One B-rep face of a CAD part: STEP entity #26644.
In plain terms, the planar face has unit normal (0, 0, -1).
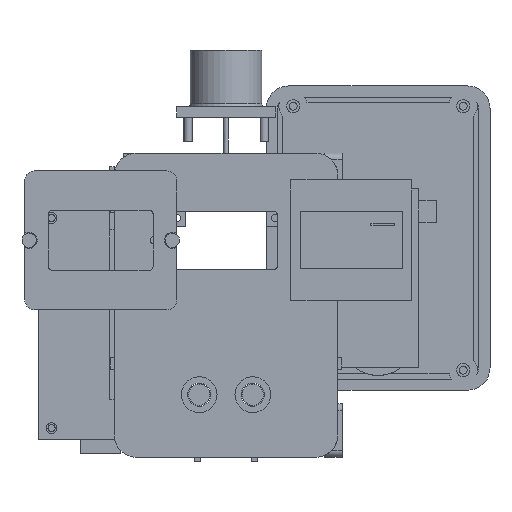
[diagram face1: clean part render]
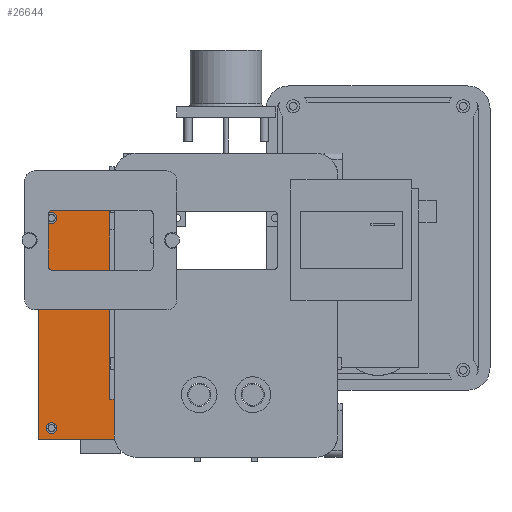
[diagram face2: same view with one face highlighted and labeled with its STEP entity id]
Its self-contained STEP definition (entity closure, numbers rounded to 3 decimals):
#26231 = VERTEX_POINT('',#26232);
#26232 = CARTESIAN_POINT('',(-14.,-30.,9.));
#26241 = PLANE('',#26242);
#26242 = AXIS2_PLACEMENT_3D('',#26243,#26244,#26245);
#26243 = CARTESIAN_POINT('',(-14.,-30.,9.));
#26244 = DIRECTION('',(1.,0.,-0.));
#26245 = DIRECTION('',(0.,0.,1.));
#26253 = PLANE('',#26254);
#26254 = AXIS2_PLACEMENT_3D('',#26255,#26256,#26257);
#26255 = CARTESIAN_POINT('',(-14.,-30.,9.));
#26256 = DIRECTION('',(-0.,1.,0.));
#26257 = DIRECTION('',(0.,0.,1.));
#26265 = EDGE_CURVE('',#26231,#26266,#26268,.T.);
#26266 = VERTEX_POINT('',#26267);
#26267 = CARTESIAN_POINT('',(-14.,22.,9.));
#26268 = SURFACE_CURVE('',#26269,(#26273,#26280),.PCURVE_S1.);
#26269 = LINE('',#26270,#26271);
#26270 = CARTESIAN_POINT('',(-14.,-30.,9.));
#26271 = VECTOR('',#26272,1.);
#26272 = DIRECTION('',(-0.,1.,0.));
#26273 = PCURVE('',#26241,#26274);
#26274 = DEFINITIONAL_REPRESENTATION('',(#26275),#26279);
#26275 = LINE('',#26276,#26277);
#26276 = CARTESIAN_POINT('',(0.,0.));
#26277 = VECTOR('',#26278,1.);
#26278 = DIRECTION('',(0.,-1.));
#26279 = ( GEOMETRIC_REPRESENTATION_CONTEXT(2) 
PARAMETRIC_REPRESENTATION_CONTEXT() REPRESENTATION_CONTEXT('2D SPACE',''
  ) );
#26280 = PCURVE('',#26281,#26286);
#26281 = PLANE('',#26282);
#26282 = AXIS2_PLACEMENT_3D('',#26283,#26284,#26285);
#26283 = CARTESIAN_POINT('',(-14.,-30.,9.));
#26284 = DIRECTION('',(0.,0.,1.));
#26285 = DIRECTION('',(1.,0.,-0.));
#26286 = DEFINITIONAL_REPRESENTATION('',(#26287),#26291);
#26287 = LINE('',#26288,#26289);
#26288 = CARTESIAN_POINT('',(0.,0.));
#26289 = VECTOR('',#26290,1.);
#26290 = DIRECTION('',(0.,1.));
#26291 = ( GEOMETRIC_REPRESENTATION_CONTEXT(2) 
PARAMETRIC_REPRESENTATION_CONTEXT() REPRESENTATION_CONTEXT('2D SPACE',''
  ) );
#26309 = PLANE('',#26310);
#26310 = AXIS2_PLACEMENT_3D('',#26311,#26312,#26313);
#26311 = CARTESIAN_POINT('',(-14.,22.,9.));
#26312 = DIRECTION('',(-0.,1.,0.));
#26313 = DIRECTION('',(0.,0.,1.));
#26350 = EDGE_CURVE('',#26231,#26351,#26353,.T.);
#26351 = VERTEX_POINT('',#26352);
#26352 = CARTESIAN_POINT('',(14.,-30.,9.));
#26353 = SURFACE_CURVE('',#26354,(#26358,#26365),.PCURVE_S1.);
#26354 = LINE('',#26355,#26356);
#26355 = CARTESIAN_POINT('',(-14.,-30.,9.));
#26356 = VECTOR('',#26357,1.);
#26357 = DIRECTION('',(1.,0.,-0.));
#26358 = PCURVE('',#26253,#26359);
#26359 = DEFINITIONAL_REPRESENTATION('',(#26360),#26364);
#26360 = LINE('',#26361,#26362);
#26361 = CARTESIAN_POINT('',(0.,0.));
#26362 = VECTOR('',#26363,1.);
#26363 = DIRECTION('',(0.,1.));
#26364 = ( GEOMETRIC_REPRESENTATION_CONTEXT(2) 
PARAMETRIC_REPRESENTATION_CONTEXT() REPRESENTATION_CONTEXT('2D SPACE',''
  ) );
#26365 = PCURVE('',#26281,#26366);
#26366 = DEFINITIONAL_REPRESENTATION('',(#26367),#26371);
#26367 = LINE('',#26368,#26369);
#26368 = CARTESIAN_POINT('',(0.,0.));
#26369 = VECTOR('',#26370,1.);
#26370 = DIRECTION('',(1.,0.));
#26371 = ( GEOMETRIC_REPRESENTATION_CONTEXT(2) 
PARAMETRIC_REPRESENTATION_CONTEXT() REPRESENTATION_CONTEXT('2D SPACE',''
  ) );
#26411 = PLANE('',#26412);
#26412 = AXIS2_PLACEMENT_3D('',#26413,#26414,#26415);
#26413 = CARTESIAN_POINT('',(14.,-30.,9.));
#26414 = DIRECTION('',(1.,0.,-0.));
#26415 = DIRECTION('',(0.,0.,1.));
#26491 = CYLINDRICAL_SURFACE('',#26492,1.2);
#26492 = AXIS2_PLACEMENT_3D('',#26493,#26494,#26495);
#26493 = CARTESIAN_POINT('',(-11.,-27.5,8.95));
#26494 = DIRECTION('',(0.,0.,1.));
#26495 = DIRECTION('',(1.,0.,-0.));
#26522 = CYLINDRICAL_SURFACE('',#26523,1.2);
#26523 = AXIS2_PLACEMENT_3D('',#26524,#26525,#26526);
#26524 = CARTESIAN_POINT('',(11.,-27.5,8.95));
#26525 = DIRECTION('',(0.,0.,1.));
#26526 = DIRECTION('',(1.,0.,-0.));
#26553 = CYLINDRICAL_SURFACE('',#26554,1.2);
#26554 = AXIS2_PLACEMENT_3D('',#26555,#26556,#26557);
#26555 = CARTESIAN_POINT('',(-11.,19.5,8.95));
#26556 = DIRECTION('',(0.,0.,1.));
#26557 = DIRECTION('',(1.,0.,-0.));
#26584 = CYLINDRICAL_SURFACE('',#26585,1.2);
#26585 = AXIS2_PLACEMENT_3D('',#26586,#26587,#26588);
#26586 = CARTESIAN_POINT('',(11.,19.5,8.95));
#26587 = DIRECTION('',(0.,0.,1.));
#26588 = DIRECTION('',(1.,0.,-0.));
#26599 = EDGE_CURVE('',#26266,#26600,#26602,.T.);
#26600 = VERTEX_POINT('',#26601);
#26601 = CARTESIAN_POINT('',(14.,22.,9.));
#26602 = SURFACE_CURVE('',#26603,(#26607,#26614),.PCURVE_S1.);
#26603 = LINE('',#26604,#26605);
#26604 = CARTESIAN_POINT('',(-14.,22.,9.));
#26605 = VECTOR('',#26606,1.);
#26606 = DIRECTION('',(1.,0.,-0.));
#26607 = PCURVE('',#26309,#26608);
#26608 = DEFINITIONAL_REPRESENTATION('',(#26609),#26613);
#26609 = LINE('',#26610,#26611);
#26610 = CARTESIAN_POINT('',(0.,0.));
#26611 = VECTOR('',#26612,1.);
#26612 = DIRECTION('',(0.,1.));
#26613 = ( GEOMETRIC_REPRESENTATION_CONTEXT(2) 
PARAMETRIC_REPRESENTATION_CONTEXT() REPRESENTATION_CONTEXT('2D SPACE',''
  ) );
#26614 = PCURVE('',#26281,#26615);
#26615 = DEFINITIONAL_REPRESENTATION('',(#26616),#26620);
#26616 = LINE('',#26617,#26618);
#26617 = CARTESIAN_POINT('',(0.,52.));
#26618 = VECTOR('',#26619,1.);
#26619 = DIRECTION('',(1.,0.));
#26620 = ( GEOMETRIC_REPRESENTATION_CONTEXT(2) 
PARAMETRIC_REPRESENTATION_CONTEXT() REPRESENTATION_CONTEXT('2D SPACE',''
  ) );
#26644 = ADVANCED_FACE('',(#26645,#26671,#26697,#26723,#26749),#26281,
  .F.);
#26645 = FACE_BOUND('',#26646,.F.);
#26646 = EDGE_LOOP('',(#26647,#26648,#26649,#26670));
#26647 = ORIENTED_EDGE('',*,*,#26265,.F.);
#26648 = ORIENTED_EDGE('',*,*,#26350,.T.);
#26649 = ORIENTED_EDGE('',*,*,#26650,.T.);
#26650 = EDGE_CURVE('',#26351,#26600,#26651,.T.);
#26651 = SURFACE_CURVE('',#26652,(#26656,#26663),.PCURVE_S1.);
#26652 = LINE('',#26653,#26654);
#26653 = CARTESIAN_POINT('',(14.,-30.,9.));
#26654 = VECTOR('',#26655,1.);
#26655 = DIRECTION('',(-0.,1.,0.));
#26656 = PCURVE('',#26281,#26657);
#26657 = DEFINITIONAL_REPRESENTATION('',(#26658),#26662);
#26658 = LINE('',#26659,#26660);
#26659 = CARTESIAN_POINT('',(28.,0.));
#26660 = VECTOR('',#26661,1.);
#26661 = DIRECTION('',(0.,1.));
#26662 = ( GEOMETRIC_REPRESENTATION_CONTEXT(2) 
PARAMETRIC_REPRESENTATION_CONTEXT() REPRESENTATION_CONTEXT('2D SPACE',''
  ) );
#26663 = PCURVE('',#26411,#26664);
#26664 = DEFINITIONAL_REPRESENTATION('',(#26665),#26669);
#26665 = LINE('',#26666,#26667);
#26666 = CARTESIAN_POINT('',(0.,0.));
#26667 = VECTOR('',#26668,1.);
#26668 = DIRECTION('',(0.,-1.));
#26669 = ( GEOMETRIC_REPRESENTATION_CONTEXT(2) 
PARAMETRIC_REPRESENTATION_CONTEXT() REPRESENTATION_CONTEXT('2D SPACE',''
  ) );
#26670 = ORIENTED_EDGE('',*,*,#26599,.F.);
#26671 = FACE_BOUND('',#26672,.F.);
#26672 = EDGE_LOOP('',(#26673));
#26673 = ORIENTED_EDGE('',*,*,#26674,.F.);
#26674 = EDGE_CURVE('',#26675,#26675,#26677,.T.);
#26675 = VERTEX_POINT('',#26676);
#26676 = CARTESIAN_POINT('',(-9.8,-27.5,9.));
#26677 = SURFACE_CURVE('',#26678,(#26683,#26690),.PCURVE_S1.);
#26678 = CIRCLE('',#26679,1.2);
#26679 = AXIS2_PLACEMENT_3D('',#26680,#26681,#26682);
#26680 = CARTESIAN_POINT('',(-11.,-27.5,9.));
#26681 = DIRECTION('',(0.,0.,1.));
#26682 = DIRECTION('',(1.,0.,-0.));
#26683 = PCURVE('',#26281,#26684);
#26684 = DEFINITIONAL_REPRESENTATION('',(#26685),#26689);
#26685 = CIRCLE('',#26686,1.2);
#26686 = AXIS2_PLACEMENT_2D('',#26687,#26688);
#26687 = CARTESIAN_POINT('',(3.,2.5));
#26688 = DIRECTION('',(1.,0.));
#26689 = ( GEOMETRIC_REPRESENTATION_CONTEXT(2) 
PARAMETRIC_REPRESENTATION_CONTEXT() REPRESENTATION_CONTEXT('2D SPACE',''
  ) );
#26690 = PCURVE('',#26491,#26691);
#26691 = DEFINITIONAL_REPRESENTATION('',(#26692),#26696);
#26692 = LINE('',#26693,#26694);
#26693 = CARTESIAN_POINT('',(0.,0.05));
#26694 = VECTOR('',#26695,1.);
#26695 = DIRECTION('',(1.,0.));
#26696 = ( GEOMETRIC_REPRESENTATION_CONTEXT(2) 
PARAMETRIC_REPRESENTATION_CONTEXT() REPRESENTATION_CONTEXT('2D SPACE',''
  ) );
#26697 = FACE_BOUND('',#26698,.F.);
#26698 = EDGE_LOOP('',(#26699));
#26699 = ORIENTED_EDGE('',*,*,#26700,.F.);
#26700 = EDGE_CURVE('',#26701,#26701,#26703,.T.);
#26701 = VERTEX_POINT('',#26702);
#26702 = CARTESIAN_POINT('',(12.2,-27.5,9.));
#26703 = SURFACE_CURVE('',#26704,(#26709,#26716),.PCURVE_S1.);
#26704 = CIRCLE('',#26705,1.2);
#26705 = AXIS2_PLACEMENT_3D('',#26706,#26707,#26708);
#26706 = CARTESIAN_POINT('',(11.,-27.5,9.));
#26707 = DIRECTION('',(0.,0.,1.));
#26708 = DIRECTION('',(1.,0.,-0.));
#26709 = PCURVE('',#26281,#26710);
#26710 = DEFINITIONAL_REPRESENTATION('',(#26711),#26715);
#26711 = CIRCLE('',#26712,1.2);
#26712 = AXIS2_PLACEMENT_2D('',#26713,#26714);
#26713 = CARTESIAN_POINT('',(25.,2.5));
#26714 = DIRECTION('',(1.,0.));
#26715 = ( GEOMETRIC_REPRESENTATION_CONTEXT(2) 
PARAMETRIC_REPRESENTATION_CONTEXT() REPRESENTATION_CONTEXT('2D SPACE',''
  ) );
#26716 = PCURVE('',#26522,#26717);
#26717 = DEFINITIONAL_REPRESENTATION('',(#26718),#26722);
#26718 = LINE('',#26719,#26720);
#26719 = CARTESIAN_POINT('',(0.,0.05));
#26720 = VECTOR('',#26721,1.);
#26721 = DIRECTION('',(1.,0.));
#26722 = ( GEOMETRIC_REPRESENTATION_CONTEXT(2) 
PARAMETRIC_REPRESENTATION_CONTEXT() REPRESENTATION_CONTEXT('2D SPACE',''
  ) );
#26723 = FACE_BOUND('',#26724,.F.);
#26724 = EDGE_LOOP('',(#26725));
#26725 = ORIENTED_EDGE('',*,*,#26726,.F.);
#26726 = EDGE_CURVE('',#26727,#26727,#26729,.T.);
#26727 = VERTEX_POINT('',#26728);
#26728 = CARTESIAN_POINT('',(-9.8,19.5,9.));
#26729 = SURFACE_CURVE('',#26730,(#26735,#26742),.PCURVE_S1.);
#26730 = CIRCLE('',#26731,1.2);
#26731 = AXIS2_PLACEMENT_3D('',#26732,#26733,#26734);
#26732 = CARTESIAN_POINT('',(-11.,19.5,9.));
#26733 = DIRECTION('',(0.,0.,1.));
#26734 = DIRECTION('',(1.,0.,-0.));
#26735 = PCURVE('',#26281,#26736);
#26736 = DEFINITIONAL_REPRESENTATION('',(#26737),#26741);
#26737 = CIRCLE('',#26738,1.2);
#26738 = AXIS2_PLACEMENT_2D('',#26739,#26740);
#26739 = CARTESIAN_POINT('',(3.,49.5));
#26740 = DIRECTION('',(1.,0.));
#26741 = ( GEOMETRIC_REPRESENTATION_CONTEXT(2) 
PARAMETRIC_REPRESENTATION_CONTEXT() REPRESENTATION_CONTEXT('2D SPACE',''
  ) );
#26742 = PCURVE('',#26553,#26743);
#26743 = DEFINITIONAL_REPRESENTATION('',(#26744),#26748);
#26744 = LINE('',#26745,#26746);
#26745 = CARTESIAN_POINT('',(0.,0.05));
#26746 = VECTOR('',#26747,1.);
#26747 = DIRECTION('',(1.,0.));
#26748 = ( GEOMETRIC_REPRESENTATION_CONTEXT(2) 
PARAMETRIC_REPRESENTATION_CONTEXT() REPRESENTATION_CONTEXT('2D SPACE',''
  ) );
#26749 = FACE_BOUND('',#26750,.F.);
#26750 = EDGE_LOOP('',(#26751));
#26751 = ORIENTED_EDGE('',*,*,#26752,.F.);
#26752 = EDGE_CURVE('',#26753,#26753,#26755,.T.);
#26753 = VERTEX_POINT('',#26754);
#26754 = CARTESIAN_POINT('',(12.2,19.5,9.));
#26755 = SURFACE_CURVE('',#26756,(#26761,#26768),.PCURVE_S1.);
#26756 = CIRCLE('',#26757,1.2);
#26757 = AXIS2_PLACEMENT_3D('',#26758,#26759,#26760);
#26758 = CARTESIAN_POINT('',(11.,19.5,9.));
#26759 = DIRECTION('',(0.,0.,1.));
#26760 = DIRECTION('',(1.,0.,-0.));
#26761 = PCURVE('',#26281,#26762);
#26762 = DEFINITIONAL_REPRESENTATION('',(#26763),#26767);
#26763 = CIRCLE('',#26764,1.2);
#26764 = AXIS2_PLACEMENT_2D('',#26765,#26766);
#26765 = CARTESIAN_POINT('',(25.,49.5));
#26766 = DIRECTION('',(1.,0.));
#26767 = ( GEOMETRIC_REPRESENTATION_CONTEXT(2) 
PARAMETRIC_REPRESENTATION_CONTEXT() REPRESENTATION_CONTEXT('2D SPACE',''
  ) );
#26768 = PCURVE('',#26584,#26769);
#26769 = DEFINITIONAL_REPRESENTATION('',(#26770),#26774);
#26770 = LINE('',#26771,#26772);
#26771 = CARTESIAN_POINT('',(0.,0.05));
#26772 = VECTOR('',#26773,1.);
#26773 = DIRECTION('',(1.,0.));
#26774 = ( GEOMETRIC_REPRESENTATION_CONTEXT(2) 
PARAMETRIC_REPRESENTATION_CONTEXT() REPRESENTATION_CONTEXT('2D SPACE',''
  ) );
